VERSION 5.7 ;
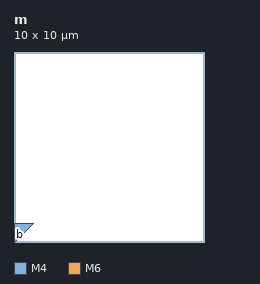
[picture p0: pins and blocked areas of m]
MACRO m
 CLASS BLOCK ;
 SIZE 10 BY 10 ;
 SYMMETRY X Y ;
 PIN a
 USE SIGNAL ;
 PORT
 LAYER M4 ;
 POLYGON 0 0 1 1 0 1 ;
 END
 END a
 PIN b
 USE SIGNAL ;
 PORT
 LAYER M6 ;
 RECT 0.000 0.000 0.032 0.028 ;
 END
 END b
END m
END LIBRARY
